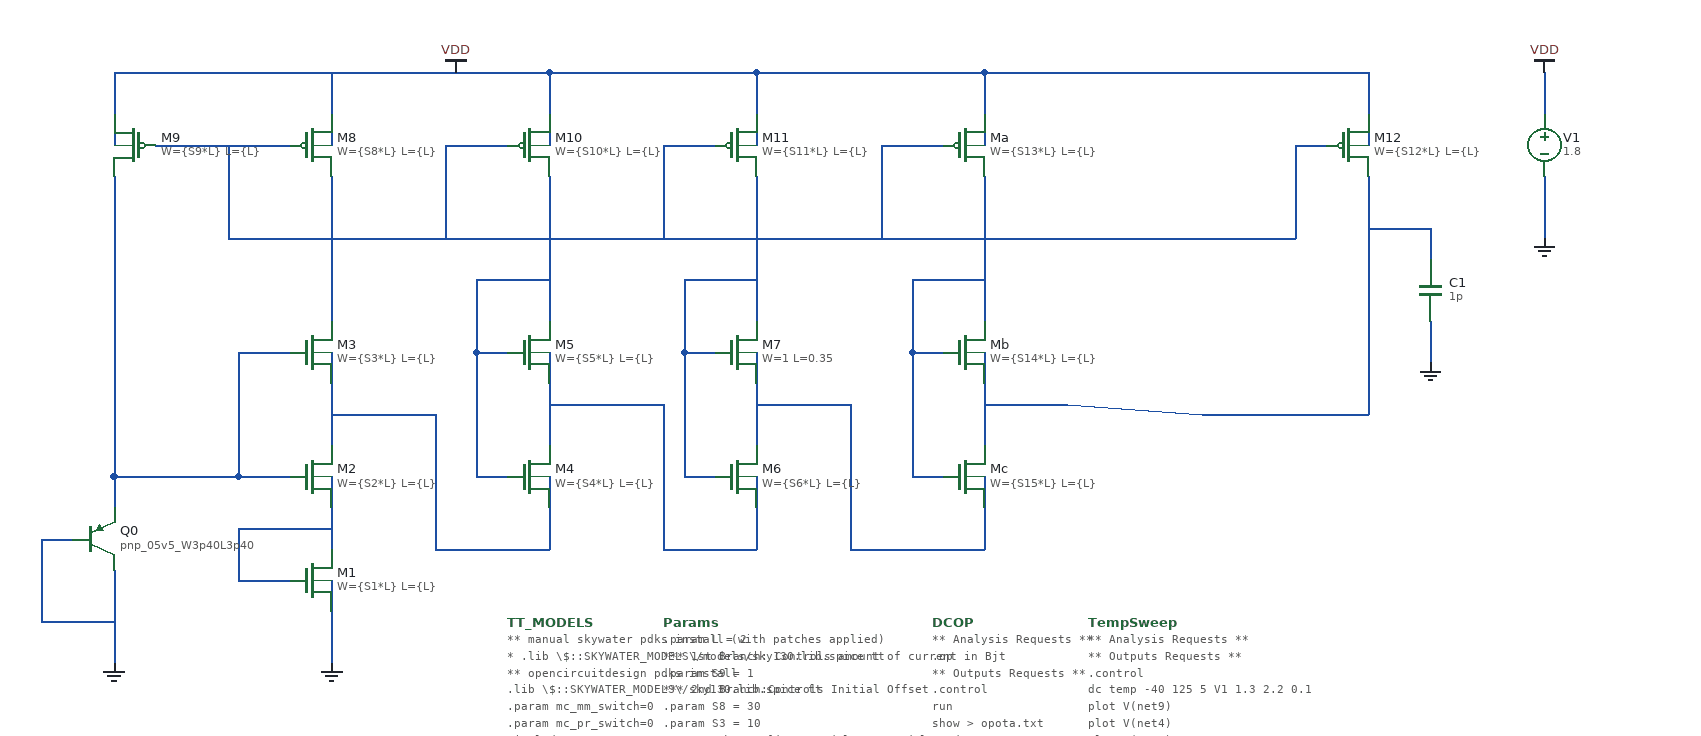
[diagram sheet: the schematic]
v {xschem version=3.0.0 file_version=1.2 }
G {}
K {}
V {}
S {}
E {}
N 640 -840 640 -790 { lab=GND}
N 640 -860 640 -840 { lab=GND}
N 640 -870 640 -860 { lab=GND}
N 640 -1060 640 -1000 { lab=#net1}
N 640 -940 640 -900 { lab=#net2}
N 550 -920 550 -870 { lab=#net2}
N 550 -920 640 -920 { lab=#net2}
N 850 -940 850 -900 { lab=#net1}
N 740 -900 850 -900 { lab=#net1}
N 740 -1030 740 -900 { lab=#net1}
N 640 -1030 740 -1030 { lab=#net1}
N 1050 -1060 1050 -1000 { lab=#net3}
N 850 -1060 850 -1000 { lab=#net4}
N 780 -970 810 -970 { lab=#net5}
N 780 -1090 780 -970 { lab=#net5}
N 780 -1090 810 -1090 { lab=#net5}
N 850 -1210 850 -1120 { lab=#net5}
N 1050 -1210 1050 -1120 { lab=#net6}
N 640 -1210 640 -1120 { lab=#net7}
N 1050 -940 1050 -900 { lab=#net4}
N 960 -900 1050 -900 { lab=#net4}
N 960 -1040 960 -900 { lab=#net4}
N 850 -1040 960 -1040 { lab=#net4}
N 980 -970 1010 -970 { lab=#net6}
N 980 -1090 980 -970 { lab=#net6}
N 980 -1090 1010 -1090 { lab=#net6}
N 980 -1160 980 -1090 { lab=#net6}
N 980 -1160 1050 -1160 { lab=#net6}
N 780 -1160 780 -1090 { lab=#net5}
N 780 -1160 850 -1160 { lab=#net5}
N 550 -1090 600 -1090 { lab=#net8}
N 550 -1090 550 -970 { lab=#net8}
N 550 -970 600 -970 { lab=#net8}
N 1640 -1260 1640 -1030 { lab=#net9}
N 470 -1290 600 -1290 { lab=#net7}
N 640 -1260 640 -1210 { lab=#net7}
N 540 -1290 540 -1200 { lab=#net7}
N 540 -1200 640 -1200 { lab=#net7}
N 850 -1260 850 -1210 { lab=#net5}
N 1050 -1260 1050 -1210 { lab=#net6}
N 440 -970 550 -970 { lab=#net8}
N 430 -970 430 -940 { lab=#net8}
N 430 -880 430 -800 { lab=GND}
N 550 -870 600 -870 { lab=#net2}
N 360 -910 390 -910 { lab=GND}
N 360 -910 360 -830 { lab=GND}
N 360 -830 430 -830 { lab=GND}
N 430 -970 440 -970 { lab=#net8}
N 430 -1260 430 -970 { lab=#net8}
N 430 -1360 760 -1360 { lab=VDD}
N 430 -1360 430 -1320 { lab=VDD}
N 640 -1360 640 -1320 { lab=VDD}
N 760 -1360 850 -1360 { lab=VDD}
N 850 -1360 850 -1320 { lab=VDD}
N 1050 -1360 1050 -1320 { lab=VDD}
N 850 -1360 1050 -1360 { lab=VDD}
N 1640 -1360 1640 -1320 { lab=VDD}
N 1050 -1360 1220 -1360 { lab=VDD}
N 1270 -1060 1270 -1000 { lab=#net9}
N 1270 -1210 1270 -1120 { lab=#net10}
N 1270 -940 1270 -900 { lab=#net3}
N 1180 -900 1270 -900 { lab=#net3}
N 1140 -1040 1140 -900 { lab=#net3}
N 1200 -970 1230 -970 { lab=#net10}
N 1200 -1090 1200 -970 { lab=#net10}
N 1200 -1090 1230 -1090 { lab=#net10}
N 1200 -1160 1200 -1090 { lab=#net10}
N 1200 -1160 1270 -1160 { lab=#net10}
N 1270 -1260 1270 -1210 { lab=#net10}
N 1270 -1360 1270 -1320 { lab=VDD}
N 1140 -900 1180 -900 { lab=#net3}
N 1220 -1360 1270 -1360 { lab=VDD}
N 1050 -1040 1140 -1040 { lab=#net3}
N 1270 -1040 1350 -1040 { lab=#net9}
N 1480 -1030 1640 -1030 { lab=#net9}
N 1480 -1360 1640 -1360 { lab=VDD}
N 1270 -1360 1430 -1360 { lab=VDD}
N 1270 -970 1270 -940 { lab=#net3}
N 1270 -1090 1270 -1060 { lab=#net9}
N 1050 -1090 1050 -1060 { lab=#net3}
N 1050 -970 1050 -940 { lab=#net4}
N 850 -970 850 -940 { lab=#net1}
N 850 -1090 850 -1060 { lab=#net4}
N 640 -1090 640 -1060 { lab=#net1}
N 640 -970 640 -940 { lab=#net2}
N 1640 -1310 1640 -1290 { lab=#net11}
N 640 -1310 640 -1290 { lab=#net12}
N 850 -1310 850 -1290 { lab=#net13}
N 1050 -1320 1050 -1290 { lab=VDD}
N 1270 -1320 1270 -1290 { lab=VDD}
N 640 -1200 1380 -1200 { lab=#net7}
N 750 -1290 810 -1290 { lab=#net7}
N 750 -1290 750 -1200 { lab=#net7}
N 960 -1290 1010 -1290 { lab=#net7}
N 960 -1290 960 -1200 { lab=#net7}
N 1170 -1290 1230 -1290 { lab=#net7}
N 1170 -1290 1170 -1200 { lab=#net7}
N 1570 -1290 1600 -1290 { lab=#net7}
N 1570 -1290 1570 -1200 { lab=#net7}
N 1380 -1200 1570 -1200 { lab=#net7}
N 1810 -1260 1810 -1200 { lab=GND}
N 1810 -1360 1810 -1320 { lab=VDD}
N 1700 -1210 1700 -1180 { lab=#net9}
N 1640 -1210 1700 -1210 { lab=#net9}
N 1700 -1120 1700 -1080 { lab=GND}
N 430 -1320 430 -1290 { lab=VDD}
N 430 -800 430 -790 { lab=GND}
N 1350 -1040 1480 -1030 { lab=#net9}
N 1430 -1360 1480 -1360 { lab=VDD}
C {sky130_fd_pr/nfet_01v8_lvt.sym} 620 -870 0 0 {name=M1
L=\{L\}
W=\{S1*L\}
nf=1
mult=1
ad="'int((nf+1)/2) * W/nf * 0.29'" 
pd="'2*int((nf+1)/2) * (W/nf + 0.29)'"
as="'int((nf+2)/2) * W/nf * 0.29'" 
ps="'2*int((nf+2)/2) * (W/nf + 0.29)'"
nrd="'0.29 / W'" nrs="'0.29 / W'"
sa=0 sb=0 sd=0
model=nfet_01v8_lvt
spiceprefix=X
}
C {devices/gnd.sym} 640 -790 0 0 {name=l3 lab=GND}
C {devices/code.sym} 1220 -830 0 0 {name=DCOP only_toplevel=false value="
** Analysis Requests **
.op
** Outputs Requests **
.control
run
show > opota.txt
.endc
"}
C {devices/code.sym} 810 -830 0 0 {name=TT_MODELS
only_toplevel=true
format="tcleval( @value )"
value="** manual skywater pdks install (with patches applied)
* .lib \\\\$::SKYWATER_MODELS\\\\/models/sky130.lib.spice tt

** opencircuitdesign pdks install
.lib \\\\$::SKYWATER_MODELS\\\\/sky130.lib.spice tt

.param mc_mm_switch=0
.param mc_pr_switch=0

.include "\\\\$::SKYWATER_MODELS\\\\/sky130_fd_pr__model__pnp.model.spice"
"
spice_ignore=false}
C {devices/launcher.sym} 1620 -920 0 0 {name=h1
descr=Annotate 
tclcommand="ngspice::annotate"}
C {devices/launcher.sym} 1600 -830 0 0 {name=h2
descr="View Raw file" 
tclcommand="textwindow $netlist_dir/test_nmos.raw"}
C {devices/launcher.sym} 1600 -830 0 0 {name=h3
descr="View Raw file" 
tclcommand="textwindow $netlist_dir/test_nmos.raw"}
C {devices/launcher.sym} 1600 -740 0 0 {name=h4
descr="View OPPoint" 
tclcommand="textwindow $netlist_dir/opota.txt"}
C {sky130_fd_pr/nfet_01v8_lvt.sym} 620 -970 0 0 {name=M2
L=\{L\}
W=\{S2*L\}
nf=1
mult=1
ad="'int((nf+1)/2) * W/nf * 0.29'" 
pd="'2*int((nf+1)/2) * (W/nf + 0.29)'"
as="'int((nf+2)/2) * W/nf * 0.29'" 
ps="'2*int((nf+2)/2) * (W/nf + 0.29)'"
nrd="'0.29 / W'" nrs="'0.29 / W'"
sa=0 sb=0 sd=0
model=nfet_01v8_lvt
spiceprefix=X
}
C {sky130_fd_pr/nfet_01v8_lvt.sym} 620 -1090 0 0 {name=M3
L=\{L\}
W=\{S3*L\}
nf=1
mult=1
ad="'int((nf+1)/2) * W/nf * 0.29'" 
pd="'2*int((nf+1)/2) * (W/nf + 0.29)'"
as="'int((nf+2)/2) * W/nf * 0.29'" 
ps="'2*int((nf+2)/2) * (W/nf + 0.29)'"
nrd="'0.29 / W'" nrs="'0.29 / W'"
sa=0 sb=0 sd=0
model=nfet_01v8_lvt
spiceprefix=X
}
C {sky130_fd_pr/nfet_01v8_lvt.sym} 830 -970 0 0 {name=M4
L=\{L\}
W=\{S4*L\}
nf=1
mult=1
ad="'int((nf+1)/2) * W/nf * 0.29'" 
pd="'2*int((nf+1)/2) * (W/nf + 0.29)'"
as="'int((nf+2)/2) * W/nf * 0.29'" 
ps="'2*int((nf+2)/2) * (W/nf + 0.29)'"
nrd="'0.29 / W'" nrs="'0.29 / W'"
sa=0 sb=0 sd=0
model=nfet_01v8_lvt
spiceprefix=X
}
C {sky130_fd_pr/nfet_01v8_lvt.sym} 830 -1090 0 0 {name=M5
L=\{L\}
W=\{S5*L\}
nf=1
mult=1
ad="'int((nf+1)/2) * W/nf * 0.29'" 
pd="'2*int((nf+1)/2) * (W/nf + 0.29)'"
as="'int((nf+2)/2) * W/nf * 0.29'" 
ps="'2*int((nf+2)/2) * (W/nf + 0.29)'"
nrd="'0.29 / W'" nrs="'0.29 / W'"
sa=0 sb=0 sd=0
model=nfet_01v8_lvt
spiceprefix=X
}
C {sky130_fd_pr/nfet_01v8_lvt.sym} 1030 -970 0 0 {name=M6
L=\{L\}
W=\{S6*L\}
nf=1
mult=1
ad="'int((nf+1)/2) * W/nf * 0.29'" 
pd="'2*int((nf+1)/2) * (W/nf + 0.29)'"
as="'int((nf+2)/2) * W/nf * 0.29'" 
ps="'2*int((nf+2)/2) * (W/nf + 0.29)'"
nrd="'0.29 / W'" nrs="'0.29 / W'"
sa=0 sb=0 sd=0
model=nfet_01v8_lvt
spiceprefix=X
}
C {sky130_fd_pr/nfet_01v8_lvt.sym} 1030 -1090 0 0 {name=M7
L=0.35
W=1
nf=1
mult=1
ad="'int((nf+1)/2) * W/nf * 0.29'" 
pd="'2*int((nf+1)/2) * (W/nf + 0.29)'"
as="'int((nf+2)/2) * W/nf * 0.29'" 
ps="'2*int((nf+2)/2) * (W/nf + 0.29)'"
nrd="'0.29 / W'" nrs="'0.29 / W'"
sa=0 sb=0 sd=0
model=nfet_01v8_lvt
spiceprefix=X
}
C {sky130_fd_pr/pfet_01v8_lvt.sym} 620 -1290 0 0 {name=M8
L=\{L\}
W=\{S8*L\}
nf=1
mult=1
ad="'int((nf+1)/2) * W/nf * 0.29'" 
pd="'2*int((nf+1)/2) * (W/nf + 0.29)'"
as="'int((nf+2)/2) * W/nf * 0.29'" 
ps="'2*int((nf+2)/2) * (W/nf + 0.29)'"
nrd="'0.29 / W'" nrs="'0.29 / W'"
sa=0 sb=0 sd=0
model=pfet_01v8_lvt
spiceprefix=X
}
C {sky130_fd_pr/pfet_01v8_lvt.sym} 450 -1290 0 1 {name=M9
L=\{L\}
W=\{S9*L\}
nf=1
mult=1
ad="'int((nf+1)/2) * W/nf * 0.29'" 
pd="'2*int((nf+1)/2) * (W/nf + 0.29)'"
as="'int((nf+2)/2) * W/nf * 0.29'" 
ps="'2*int((nf+2)/2) * (W/nf + 0.29)'"
nrd="'0.29 / W'" nrs="'0.29 / W'"
sa=0 sb=0 sd=0
model=pfet_01v8_lvt
spiceprefix=X
}
C {sky130_fd_pr/pfet_01v8_lvt.sym} 830 -1290 0 0 {name=M10
L=\{L\}
W=\{S10*L\}
nf=1
mult=1
ad="'int((nf+1)/2) * W/nf * 0.29'" 
pd="'2*int((nf+1)/2) * (W/nf + 0.29)'"
as="'int((nf+2)/2) * W/nf * 0.29'" 
ps="'2*int((nf+2)/2) * (W/nf + 0.29)'"
nrd="'0.29 / W'" nrs="'0.29 / W'"
sa=0 sb=0 sd=0
model=pfet_01v8_lvt
spiceprefix=X
}
C {sky130_fd_pr/pfet_01v8_lvt.sym} 1030 -1290 0 0 {name=M11
L=\{L\}
W=\{S11*L\}
nf=1
mult=1
ad="'int((nf+1)/2) * W/nf * 0.29'" 
pd="'2*int((nf+1)/2) * (W/nf + 0.29)'"
as="'int((nf+2)/2) * W/nf * 0.29'" 
ps="'2*int((nf+2)/2) * (W/nf + 0.29)'"
nrd="'0.29 / W'" nrs="'0.29 / W'"
sa=0 sb=0 sd=0
model=pfet_01v8_lvt
spiceprefix=X
}
C {sky130_fd_pr/pfet_01v8_lvt.sym} 1620 -1290 0 0 {name=M12
L=\{L\}
W=\{S12*L\}
nf=1
mult=1
ad="'int((nf+1)/2) * W/nf * 0.29'" 
pd="'2*int((nf+1)/2) * (W/nf + 0.29)'"
as="'int((nf+2)/2) * W/nf * 0.29'" 
ps="'2*int((nf+2)/2) * (W/nf + 0.29)'"
nrd="'0.29 / W'" nrs="'0.29 / W'"
sa=0 sb=0 sd=0
model=pfet_01v8_lvt
spiceprefix=X
}
C {sky130_fd_pr/pnp_05v5.sym} 410 -910 0 0 {name=Q0
model=pnp_05v5_W3p40L3p40
spiceprefix=X
}
C {devices/vdd.sym} 760 -1360 0 0 {name=l2 lab=VDD}
C {sky130_fd_pr/nfet_01v8_lvt.sym} 1250 -970 0 0 {name=Mc
L=\{L\}
W=\{S15*L\}
nf=1
mult=1
ad="'int((nf+1)/2) * W/nf * 0.29'" 
pd="'2*int((nf+1)/2) * (W/nf + 0.29)'"
as="'int((nf+2)/2) * W/nf * 0.29'" 
ps="'2*int((nf+2)/2) * (W/nf + 0.29)'"
nrd="'0.29 / W'" nrs="'0.29 / W'"
sa=0 sb=0 sd=0
model=nfet_01v8_lvt
spiceprefix=X
}
C {sky130_fd_pr/nfet_01v8_lvt.sym} 1250 -1090 0 0 {name=Mb
L=\{L\}
W=\{S14*L\}
nf=1
mult=1
ad="'int((nf+1)/2) * W/nf * 0.29'" 
pd="'2*int((nf+1)/2) * (W/nf + 0.29)'"
as="'int((nf+2)/2) * W/nf * 0.29'" 
ps="'2*int((nf+2)/2) * (W/nf + 0.29)'"
nrd="'0.29 / W'" nrs="'0.29 / W'"
sa=0 sb=0 sd=0
model=nfet_01v8_lvt
spiceprefix=X
}
C {sky130_fd_pr/pfet_01v8_lvt.sym} 1250 -1290 0 0 {name=Ma
L=\{L\}
W=\{S13*L\}
nf=1
mult=1
ad="'int((nf+1)/2) * W/nf * 0.29'" 
pd="'2*int((nf+1)/2) * (W/nf + 0.29)'"
as="'int((nf+2)/2) * W/nf * 0.29'" 
ps="'2*int((nf+2)/2) * (W/nf + 0.29)'"
nrd="'0.29 / W'" nrs="'0.29 / W'"
sa=0 sb=0 sd=0
model=pfet_01v8_lvt
spiceprefix=X
}
C {devices/vdd.sym} 1810 -1360 0 0 {name=l4 lab=VDD}
C {devices/gnd.sym} 1810 -1200 0 0 {name=l5 lab=GND}
C {devices/vsource.sym} 1810 -1290 0 0 {name=V1 value=1.8
}
C {devices/code.sym} 1370 -830 0 0 {name=TempSweep only_toplevel=false value="
** Analysis Requests **
** Outputs Requests **
.control
dc temp -40 125 5 V1 1.3 2.2 0.1
plot V(net9)
plot V(net4)
plot V(net1)
plot V(net8)
.endc
"}
C {devices/code.sym} 960 -830 0 0 {name=Params only_toplevel=false value="
.param L = 2

*** 1st Branch: Controls amount of current in Bjt
.param S9 = 1

*** 2nd Branch:Controls Initial Offset
.param S8 = 30
.param S3 = 10
.param S2 = 10
.param S1 = 10

*** 3rd, 4th, 5th Branches: Fine Tuning slope for PTAT slope
.param S10 = 1
.param S5 = 20
.param S4 = 1

.param S11 = 1
.param S7 = 20
.param S6 = 1


.param S13 = 1
.param S14 = 20
.param S15 = 1

*.param S16 = 1
*.param S17 = 20
*.param S18 = 1

*** Branch 6: Coarse Tuning for PTAT Slope
.param S12 = 5
"}
C {devices/capa.sym} 1700 -1150 0 0 {name=C1
m=1
value=1p
footprint=1206
device="ceramic capacitor"}
C {devices/gnd.sym} 1700 -1080 0 0 {name=l6 lab=GND}
C {devices/gnd.sym} 430 -790 0 0 {name=l1 lab=GND}
